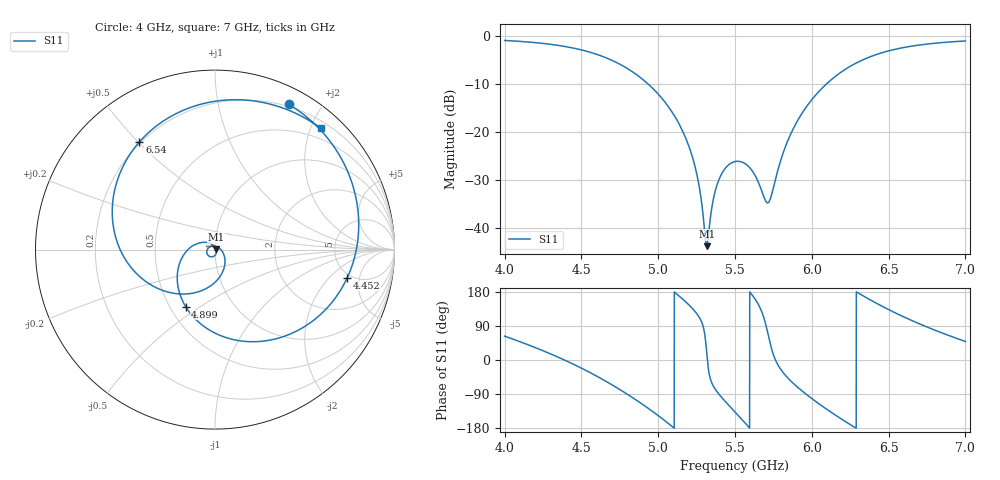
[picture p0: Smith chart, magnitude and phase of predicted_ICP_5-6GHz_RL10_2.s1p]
! ICP-predicted S11, target 5.000-6.000 GHz at -10 dB. Complex ensemble mean (passive and causal);
! its |S11| can differ slightly from the dB-domain mean reported in designs.csv.
!  Air_gap = 2.58mm
!  W_Patch = 12.33mm
!  L_Patch = 18.16mm
!  Sx = 0.91mm
!  Sy = 1.53mm
!  W_Patch1 = 10.15mm
!  WS = 0.71mm
!  Curve_Amp1 = 0.74mm
!  Extra = 5.46mm
# GHz S MA R 50
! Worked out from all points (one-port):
!   3001 points, 4 GHz to 7 GHz, reference 50 ohm
!   lowest |S11| = -43.7 dB at 5.316 GHz (marker M1), VSWR 1.01, Z = 50.6 + j0.195 ohm
!   |S11| at or under -10 dB: 4.937 GHz to 6.092 GHz (1.155 GHz wide, 20.9 % of centre)
!   S11 on the Smith chart (normalised r, x): 4 GHz: 0.18, +1.62; 4.452 GHz: 4.63, -3.34; 4.899 GHz: 0.60, -0.44; 6.54 GHz: 0.19, +0.50; 7 GHz: 0.31, +2.16
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4  0.908 63.0
4.209  0.8591 31.2
4.375  0.7945 2.6
4.452  0.7535 -11.9
4.612  0.6409 -45.3
4.75  0.5139 -77.9
4.899  0.3572 -117.3
5.002  0.2488 -147.3
5.125  0.1322 172.8
5.24  0.04399 127.9
5.27  0.0256 110.8
5.305  0.008449 62.1
5.316  0.006536 17.1
5.36  0.02051 -69.6
5.39  0.03062 -87.5
5.439  0.04276 -110.5
5.5  0.04974 -136.9
5.601  0.04199 177.2
5.715  0.01849 68.1
5.813  0.06085 -33.0
5.875  0.1059 -59.9
6.084  0.3074 -126.3
6.25  0.4881 -170.4
6.392  0.6244 156.1
6.54  0.7331 125.0
6.625  0.7801 108.9
6.8  0.8492 78.9
7  0.8968 48.9
